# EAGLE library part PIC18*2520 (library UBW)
PIC18*2520 Microchip FLASH Microcontroller with A/D DEVICE FEATURES FeaturePIC18*2520 Program Memory (bytes) 32768 Program Memory (instructions) 16384 Interupt Sources 19 I/O Ports Ports A, B, C, (E) Capture/Compare/PWM Modules 2 Enhanced Capture/Compare/PWM Modules 0 Parallel Communications (PSP) No 10-bit Analog-to-Digital Module 10 input Channels Package Types 28-pin PDIP 28-pin SOIC 28-pin QFN NOTES: F only after 18, means standard voltage range from 4.2v to 5.5v LF after 18, means extended voltage range from 2.0v to 5.5v -E before / denotes extended temperature range from -40&deg;C to +120&deg;C -I before / denotes industrial temperature range from -40&deg;C to +85&deg;C /PT suffix denotes TQFP package /SO suffix denotes SOIC package /SP suffix denotes Skinny Plastic DIP package /P suffix denotes Plastic DIP package /ML suffix denotes QFN package

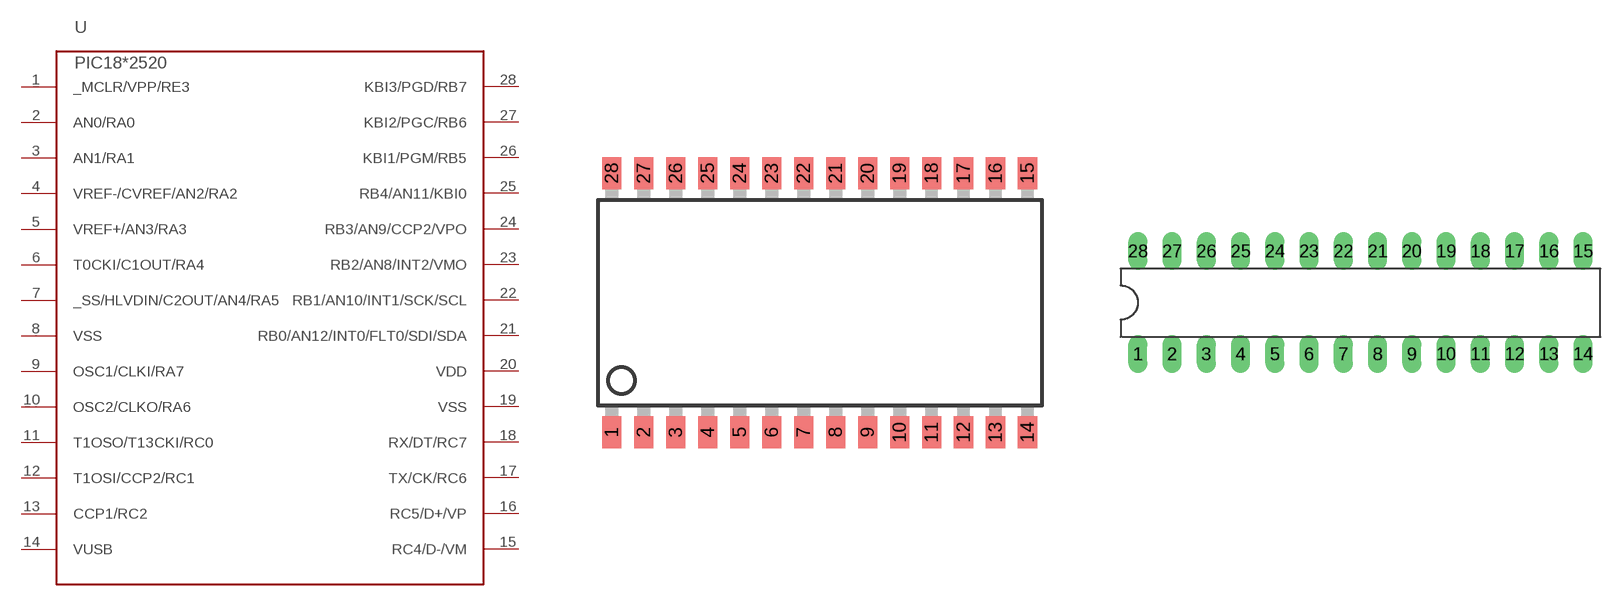
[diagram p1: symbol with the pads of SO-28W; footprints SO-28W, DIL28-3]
Designator prefix -

## PIC18F2520-I/SO, PIC18LF2520-I/SO  [SO-28W]
1  _MCLR/VPP/RE3  in
2  AN0/RA0
3  AN1/RA1
4  VREF-/CVREF/AN2/RA2
5  VREF+/AN3/RA3
6  T0CKI/C1OUT/RA4
7  _SS/HLVDIN/C2OUT/AN4/RA5
8  VSS  pwr
9  OSC1/CLKI/RA7
10  OSC2/CLKO/RA6
11  T1OSO/T13CKI/RC0
12  T1OSI/CCP2/RC1
13  CCP1/RC2
14  VUSB
15  RC4/D-/VM
16  RC5/D+/VP
17  TX/CK/RC6
18  RX/DT/RC7
19  VSS  pwr
20  VDD  pwr
21  RB0/AN12/INT0/FLT0/SDI/SDA
22  RB1/AN10/INT1/SCK/SCL
23  RB2/AN8/INT2/VMO
24  RB3/AN9/CCP2/VPO
25  RB4/AN11/KBI0
26  KBI1/PGM/RB5
27  KBI2/PGC/RB6
28  KBI3/PGD/RB7

## PIC18F2520-E/SO, PIC18LF2520-E/SO  [SO-28W]
Pads as for SO-28W

## PIC18F2520-I/SP, PIC18LF2520-I/SP  [DIL28-3]
Pads as for SO-28W

## PIC18F2520-E/SP, PIC18LF2520-E/SP  [DIL28-3]
Pads as for SO-28W

## Footprint SO-28W (pad centres in mm)
Small Outline Wide Plastic Gull Wing 300-mil body, package type SO
smd 0.762 x 1.27: 1 -7.62,-5.207; 2 -6.35,-5.207; 3 -5.08,-5.207; 4 -3.81,-5.207; 5 -2.54,-5.207; 6 -1.27,-5.207; 7 0,-5.207; 8 1.27,-5.207; 9 2.54,-5.207; 10 3.81,-5.207; 11 5.08,-5.207; 12 6.35,-5.207; 13 7.62,-5.207; 14 8.89,-5.207; 15 8.89,5.08; 16 7.62,5.08; 17 6.35,5.08; 18 5.08,5.08; 19 3.81,5.08; 20 2.54,5.08; 21 1.27,5.08; 22 0,5.08; 23 -1.27,5.08; 24 -2.54,5.08; 25 -3.81,5.08; 26 -5.08,5.08; 27 -6.35,5.08; 28 -7.62,5.08

## Footprint DIL28-3 (pad centres in mm)
Dual In Line package type SP
drill 0.9 long: 1 -16.51,-3.81; 2 -13.97,-3.81; 3 -11.43,-3.81; 4 -8.89,-3.81; 5 -6.35,-3.81; 6 -3.81,-3.81; 7 -1.27,-3.81; 8 1.27,-3.81; 9 3.81,-3.81; 10 6.35,-3.81; 11 8.89,-3.81; 12 11.43,-3.81; 13 13.97,-3.81; 14 16.51,-3.81; 15 16.51,3.81; 16 13.97,3.81; 17 11.43,3.81; 18 8.89,3.81; 19 6.35,3.81; 20 3.81,3.81; 21 1.27,3.81; 22 -1.27,3.81; 23 -3.81,3.81; 24 -6.35,3.81; 25 -8.89,3.81; 26 -11.43,3.81; 27 -13.97,3.81; 28 -16.51,3.81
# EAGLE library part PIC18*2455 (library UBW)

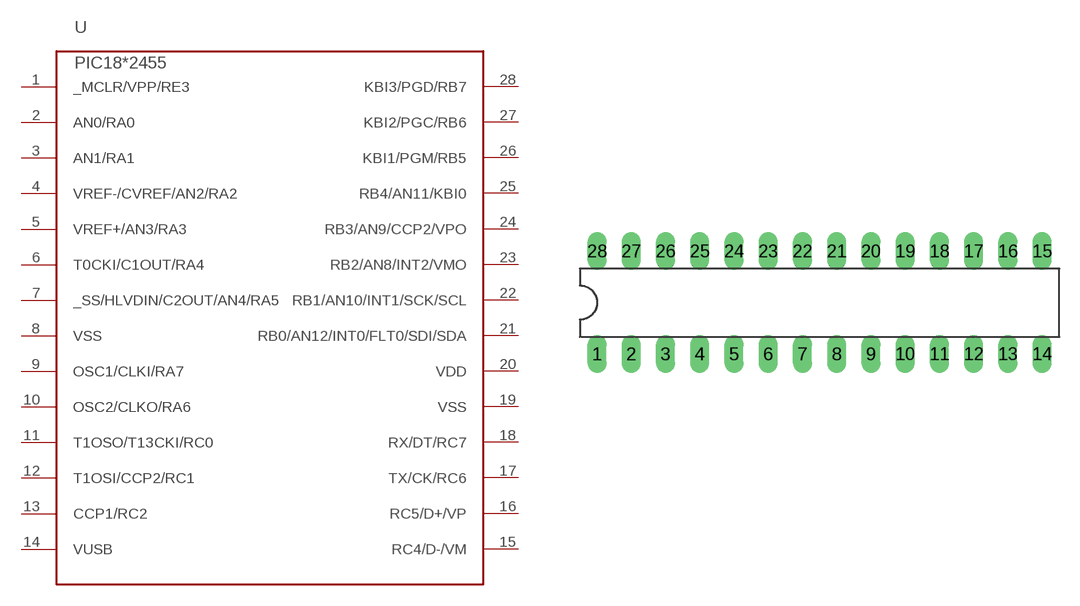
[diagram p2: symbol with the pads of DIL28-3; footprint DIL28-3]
Designator prefix -

## PIC182455  [DIL28-3]
1  _MCLR/VPP/RE3  in
2  AN0/RA0
3  AN1/RA1
4  VREF-/CVREF/AN2/RA2
5  VREF+/AN3/RA3
6  T0CKI/C1OUT/RA4
7  _SS/HLVDIN/C2OUT/AN4/RA5
8  VSS  pwr
9  OSC1/CLKI/RA7
10  OSC2/CLKO/RA6
11  T1OSO/T13CKI/RC0
12  T1OSI/CCP2/RC1
13  CCP1/RC2
14  VUSB
15  RC4/D-/VM
16  RC5/D+/VP
17  TX/CK/RC6
18  RX/DT/RC7
19  VSS  pwr
20  VDD  pwr
21  RB0/AN12/INT0/FLT0/SDI/SDA
22  RB1/AN10/INT1/SCK/SCL
23  RB2/AN8/INT2/VMO
24  RB3/AN9/CCP2/VPO
25  RB4/AN11/KBI0
26  KBI1/PGM/RB5
27  KBI2/PGC/RB6
28  KBI3/PGD/RB7

## Footprint DIL28-3 (pad centres in mm)
Dual In Line package type SP
drill 0.9 long: 1 -16.51,-3.81; 2 -13.97,-3.81; 3 -11.43,-3.81; 4 -8.89,-3.81; 5 -6.35,-3.81; 6 -3.81,-3.81; 7 -1.27,-3.81; 8 1.27,-3.81; 9 3.81,-3.81; 10 6.35,-3.81; 11 8.89,-3.81; 12 11.43,-3.81; 13 13.97,-3.81; 14 16.51,-3.81; 15 16.51,3.81; 16 13.97,3.81; 17 11.43,3.81; 18 8.89,3.81; 19 6.35,3.81; 20 3.81,3.81; 21 1.27,3.81; 22 -1.27,3.81; 23 -3.81,3.81; 24 -6.35,3.81; 25 -8.89,3.81; 26 -11.43,3.81; 27 -13.97,3.81; 28 -16.51,3.81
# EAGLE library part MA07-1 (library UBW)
PIN HEADER

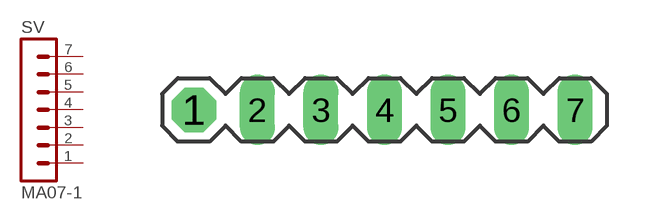
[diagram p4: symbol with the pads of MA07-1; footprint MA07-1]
Designator prefix SV

## MA07-1  [MA07-1]
1  1  pas
2  2  pas
3  3  pas
4  4  pas
5  5  pas
6  6  pas
7  7  pas

## Footprint MA07-1 (pad centres in mm)
PIN HEADER
drill 0.9 pad 1.778 octagon: 1 -7.62,0
drill 0.9 long: 2 -5.08,0; 3 -2.54,0; 4 0,0; 5 2.54,0; 6 5.08,0; 7 7.62,0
